VERSION 5.7 ;
  NOWIREEXTENSIONATPIN ON ;
  DIVIDERCHAR "/" ;
  BUSBITCHARS "[]" ;
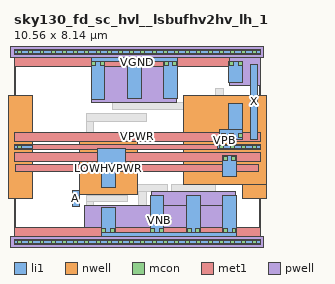
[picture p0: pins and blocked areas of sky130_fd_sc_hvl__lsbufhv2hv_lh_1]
MACRO sky130_fd_sc_hvl__lsbufhv2hv_lh_1
  CLASS BLOCK ;
  FOREIGN sky130_fd_sc_hvl__lsbufhv2hv_lh_1 ;
  ORIGIN 0.000 0.000 ;
  SIZE 10.560 BY 8.140 ;
  PIN A
    ANTENNAGATEAREA 0.750000 ;
    PORT
      LAYER li1 ;
        RECT 2.495 1.530 2.805 2.200 ;
    END
  END A
  PIN LOWHVPWR
    ANTENNADIFFAREA 1.277900 ;
    PORT
      LAYER nwell ;
        RECT 2.800 2.015 5.270 4.315 ;
      LAYER li1 ;
        RECT 3.590 3.355 4.780 4.025 ;
        RECT 3.740 2.325 4.330 3.355 ;
      LAYER mcon ;
        RECT 3.770 3.050 3.940 3.220 ;
        RECT 4.130 3.050 4.300 3.220 ;
      LAYER met1 ;
        RECT 0.070 3.020 10.490 3.305 ;
    END
  END LOWHVPWR
  PIN VGND
    USE GROUND ;
    PORT
      LAYER li1 ;
        RECT 3.300 7.715 7.010 7.885 ;
        RECT 3.300 6.085 3.890 7.715 ;
        RECT 4.860 6.165 5.450 7.715 ;
        RECT 6.420 6.165 7.010 7.715 ;
        RECT 9.210 6.835 9.800 7.745 ;
      LAYER mcon ;
        RECT 3.330 7.545 3.500 7.715 ;
        RECT 3.690 7.545 3.860 7.715 ;
        RECT 4.890 7.545 5.060 7.715 ;
        RECT 5.250 7.545 5.420 7.715 ;
        RECT 6.450 7.545 6.620 7.715 ;
        RECT 6.810 7.545 6.980 7.715 ;
        RECT 9.240 7.545 9.410 7.715 ;
        RECT 9.600 7.545 9.770 7.715 ;
      LAYER met1 ;
        RECT 0.000 7.515 10.560 7.885 ;
    END
    PORT
      LAYER li1 ;
        RECT 3.740 0.425 4.330 1.475 ;
        RECT 5.830 0.425 6.420 1.975 ;
        RECT 7.390 0.425 7.980 1.975 ;
        RECT 8.950 0.425 9.540 1.975 ;
        RECT 3.740 0.255 9.540 0.425 ;
      LAYER mcon ;
        RECT 3.770 0.425 3.940 0.595 ;
        RECT 4.130 0.425 4.300 0.595 ;
        RECT 5.860 0.425 6.030 0.595 ;
        RECT 6.220 0.425 6.390 0.595 ;
        RECT 7.420 0.425 7.590 0.595 ;
        RECT 7.780 0.425 7.950 0.595 ;
        RECT 8.980 0.425 9.150 0.595 ;
        RECT 9.340 0.425 9.510 0.595 ;
      LAYER met1 ;
        RECT 0.000 0.255 10.560 0.625 ;
    END
  END VGND
  PIN VNB
    ANTENNADIFFAREA 1.795200 ;
    PORT
      LAYER pwell ;
        RECT 5.870 1.585 9.500 2.165 ;
        RECT 3.000 0.215 9.500 1.585 ;
        RECT -0.130 -0.215 10.690 0.215 ;
      LAYER li1 ;
        RECT 0.000 -0.085 10.560 0.085 ;
      LAYER mcon ;
        RECT 0.155 -0.085 0.325 0.085 ;
        RECT 0.635 -0.085 0.805 0.085 ;
        RECT 1.115 -0.085 1.285 0.085 ;
        RECT 1.595 -0.085 1.765 0.085 ;
        RECT 2.075 -0.085 2.245 0.085 ;
        RECT 2.555 -0.085 2.725 0.085 ;
        RECT 3.035 -0.085 3.205 0.085 ;
        RECT 3.515 -0.085 3.685 0.085 ;
        RECT 3.995 -0.085 4.165 0.085 ;
        RECT 4.475 -0.085 4.645 0.085 ;
        RECT 4.955 -0.085 5.125 0.085 ;
        RECT 5.435 -0.085 5.605 0.085 ;
        RECT 5.915 -0.085 6.085 0.085 ;
        RECT 6.395 -0.085 6.565 0.085 ;
        RECT 6.875 -0.085 7.045 0.085 ;
        RECT 7.355 -0.085 7.525 0.085 ;
        RECT 7.835 -0.085 8.005 0.085 ;
        RECT 8.315 -0.085 8.485 0.085 ;
        RECT 8.795 -0.085 8.965 0.085 ;
        RECT 9.275 -0.085 9.445 0.085 ;
        RECT 9.755 -0.085 9.925 0.085 ;
        RECT 10.235 -0.085 10.405 0.085 ;
      LAYER met1 ;
        RECT 0.000 -0.115 10.560 0.115 ;
    END
    PORT
      LAYER pwell ;
        RECT -0.130 7.925 10.690 8.355 ;
        RECT 3.340 5.975 6.970 7.925 ;
        RECT 9.250 6.725 10.540 7.925 ;
      LAYER li1 ;
        RECT 0.000 8.055 10.560 8.225 ;
      LAYER mcon ;
        RECT 0.155 8.055 0.325 8.225 ;
        RECT 0.635 8.055 0.805 8.225 ;
        RECT 1.115 8.055 1.285 8.225 ;
        RECT 1.595 8.055 1.765 8.225 ;
        RECT 2.075 8.055 2.245 8.225 ;
        RECT 2.555 8.055 2.725 8.225 ;
        RECT 3.035 8.055 3.205 8.225 ;
        RECT 3.515 8.055 3.685 8.225 ;
        RECT 3.995 8.055 4.165 8.225 ;
        RECT 4.475 8.055 4.645 8.225 ;
        RECT 4.955 8.055 5.125 8.225 ;
        RECT 5.435 8.055 5.605 8.225 ;
        RECT 5.915 8.055 6.085 8.225 ;
        RECT 6.395 8.055 6.565 8.225 ;
        RECT 6.875 8.055 7.045 8.225 ;
        RECT 7.355 8.055 7.525 8.225 ;
        RECT 7.835 8.055 8.005 8.225 ;
        RECT 8.315 8.055 8.485 8.225 ;
        RECT 8.795 8.055 8.965 8.225 ;
        RECT 9.275 8.055 9.445 8.225 ;
        RECT 9.755 8.055 9.925 8.225 ;
        RECT 10.235 8.055 10.405 8.225 ;
      LAYER met1 ;
        RECT 0.000 8.025 10.560 8.255 ;
    END
  END VNB
  PIN VPB
    ANTENNADIFFAREA 0.400350 ;
    PORT
      LAYER nwell ;
        RECT -0.330 1.885 0.800 6.255 ;
        RECT 7.270 2.465 10.890 6.255 ;
        RECT 9.800 1.885 10.890 2.465 ;
      LAYER li1 ;
        RECT 0.000 3.985 0.800 4.155 ;
        RECT 8.715 3.985 10.560 4.155 ;
      LAYER mcon ;
        RECT 0.155 3.985 0.325 4.155 ;
        RECT 8.795 3.985 8.965 4.155 ;
        RECT 9.275 3.985 9.445 4.155 ;
        RECT 9.755 3.985 9.925 4.155 ;
        RECT 10.235 3.985 10.405 4.155 ;
      LAYER met1 ;
        RECT 0.000 3.955 10.560 4.185 ;
    END
  END VPB
  PIN VPWR
    USE POWER ;
    PORT
      LAYER li1 ;
        RECT 9.210 4.800 9.800 5.945 ;
        RECT 8.790 4.405 9.800 4.800 ;
      LAYER mcon ;
        RECT 8.880 4.495 9.050 4.665 ;
        RECT 9.240 4.495 9.410 4.665 ;
        RECT 9.600 4.495 9.770 4.665 ;
      LAYER met1 ;
        RECT 0.000 4.325 10.560 4.695 ;
    END
    PORT
      LAYER li1 ;
        RECT 8.940 2.795 9.530 3.705 ;
      LAYER mcon ;
        RECT 8.970 3.475 9.140 3.645 ;
        RECT 9.330 3.475 9.500 3.645 ;
      LAYER met1 ;
        RECT 0.000 3.445 10.560 3.815 ;
    END
  END VPWR
  PIN X
    ANTENNADIFFAREA 0.596250 ;
    PORT
      LAYER li1 ;
        RECT 10.120 4.405 10.450 7.625 ;
    END
  END X
  OBS
      LAYER li1 ;
        RECT 4.210 5.995 4.540 7.545 ;
        RECT 5.770 5.995 6.100 7.545 ;
        RECT 4.210 5.665 7.930 5.995 ;
        RECT 3.090 5.165 5.660 5.495 ;
        RECT 3.090 1.995 3.420 5.165 ;
        RECT 7.600 3.935 7.930 5.665 ;
        RECT 8.635 5.535 8.965 6.555 ;
        RECT 8.215 5.205 8.965 5.535 ;
        RECT 7.375 3.605 8.045 3.935 ;
        RECT 7.600 3.125 7.930 3.435 ;
        RECT 8.215 3.125 8.545 5.205 ;
        RECT 4.650 2.475 4.980 3.115 ;
        RECT 7.600 2.795 8.545 3.125 ;
        RECT 8.215 2.475 8.545 2.795 ;
        RECT 4.650 2.165 6.570 2.475 ;
        RECT 5.330 2.145 6.570 2.165 ;
        RECT 6.740 2.145 8.630 2.475 ;
        RECT 3.090 1.745 4.845 1.995 ;
        RECT 3.090 0.685 3.420 1.745 ;
        RECT 5.330 1.475 5.660 2.145 ;
        RECT 4.650 1.145 5.660 1.475 ;
        RECT 4.650 0.685 4.980 1.145 ;
        RECT 6.740 0.595 7.070 2.145 ;
        RECT 8.300 0.595 8.630 2.145 ;
  END
END sky130_fd_sc_hvl__lsbufhv2hv_lh_1
END LIBRARY

